VERSION 5.8 ;
BUSBITCHARS "[]" ;
DIVIDERCHAR "/" ;
UNITS DATABASE MICRONS 1000 ; END UNITS
MANUFACTURINGGRID 0.005 ;
LAYER metal1 TYPE ROUTING ; DIRECTION HORIZONTAL ; PITCH 0.2 ; WIDTH 0.1 ; SPACING 0.1 ; END metal1
SITE core CLASS CORE ; SIZE 1 BY 1 ; SYMMETRY Y ; END core
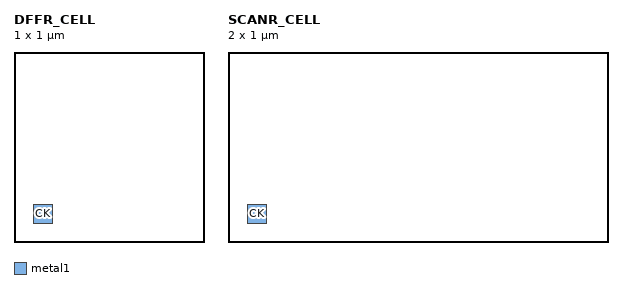
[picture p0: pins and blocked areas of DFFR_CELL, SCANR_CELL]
MACRO DFFR_CELL
CLASS CORE ;
ORIGIN 0 0 ;
SIZE 1 BY 1 ;
SYMMETRY X Y ;
SITE core ;
PIN CK
DIRECTION INPUT ;
USE CLOCK ;
PORT LAYER metal1 ; RECT 0.1 0.1 0.2 0.2 ; END
END CK
PIN RN
DIRECTION INPUT ;
USE SIGNAL ;
PORT LAYER metal1 ; RECT 0.1 0.1 0.2 0.2 ; END
END RN
PIN D
DIRECTION INPUT ;
USE SIGNAL ;
PORT LAYER metal1 ; RECT 0.1 0.1 0.2 0.2 ; END
END D
PIN Q
DIRECTION OUTPUT ;
USE SIGNAL ;
PORT LAYER metal1 ; RECT 0.1 0.1 0.2 0.2 ; END
END Q
END DFFR_CELL
MACRO SCANR_CELL
CLASS CORE ;
ORIGIN 0 0 ;
SIZE 2 BY 1 ;
SYMMETRY X Y ;
SITE core ;
PIN CK
DIRECTION INPUT ;
USE CLOCK ;
PORT LAYER metal1 ; RECT 0.1 0.1 0.2 0.2 ; END
END CK
PIN RN
DIRECTION INPUT ;
USE SIGNAL ;
PORT LAYER metal1 ; RECT 0.1 0.1 0.2 0.2 ; END
END RN
PIN D
DIRECTION INPUT ;
USE SIGNAL ;
PORT LAYER metal1 ; RECT 0.1 0.1 0.2 0.2 ; END
END D
PIN SI
DIRECTION INPUT ;
USE SIGNAL ;
PORT LAYER metal1 ; RECT 0.1 0.1 0.2 0.2 ; END
END SI
PIN SE
DIRECTION INPUT ;
USE SIGNAL ;
PORT LAYER metal1 ; RECT 0.1 0.1 0.2 0.2 ; END
END SE
PIN Q
DIRECTION OUTPUT ;
USE SIGNAL ;
PORT LAYER metal1 ; RECT 0.1 0.1 0.2 0.2 ; END
END Q
END SCANR_CELL
END LIBRARY
